VERSION 5.7 ;
  NOWIREEXTENSIONATPIN ON ;
  DIVIDERCHAR "/" ;
  BUSBITCHARS "[]" ;
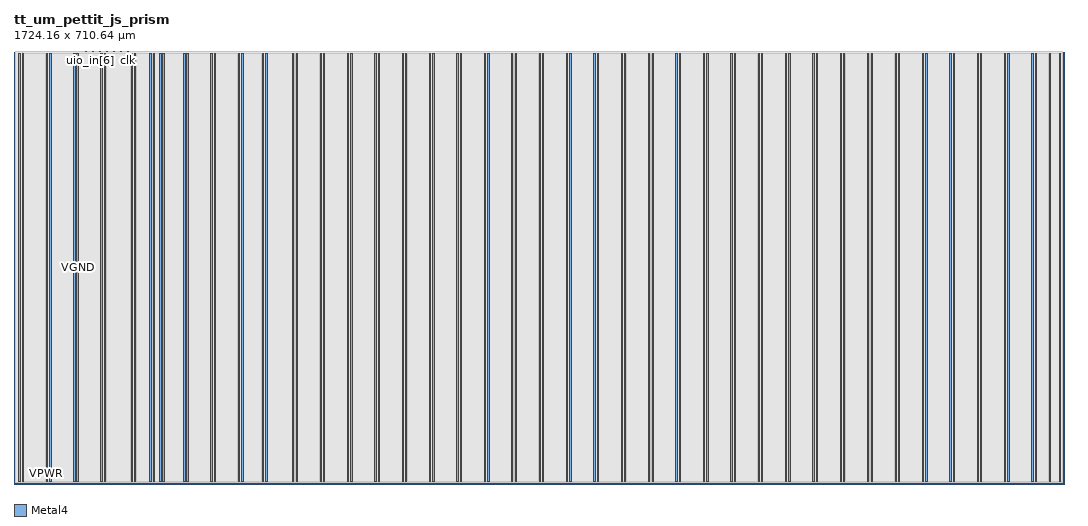
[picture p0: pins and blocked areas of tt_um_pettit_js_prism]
MACRO tt_um_pettit_js_prism
  CLASS BLOCK ;
  FOREIGN tt_um_pettit_js_prism ;
  ORIGIN 0.000 0.000 ;
  SIZE 1724.160 BY 710.640 ;
  PIN VGND
    DIRECTION INOUT ;
    USE GROUND ;
    PORT
      LAYER Metal4 ;
        RECT 13.240 3.780 16.050 706.860 ;
    END
    PORT
      LAYER Metal4 ;
        RECT 58.200 3.780 61.010 706.860 ;
    END
    PORT
      LAYER Metal4 ;
        RECT 103.160 3.780 105.970 706.860 ;
    END
    PORT
      LAYER Metal4 ;
        RECT 148.120 3.780 150.930 706.860 ;
    END
    PORT
      LAYER Metal4 ;
        RECT 192.250 3.780 195.060 706.860 ;
    END
    PORT
      LAYER Metal4 ;
        RECT 228.300 3.780 231.110 706.860 ;
    END
    PORT
      LAYER Metal4 ;
        RECT 238.710 3.780 241.520 706.860 ;
    END
    PORT
      LAYER Metal4 ;
        RECT 283.670 3.780 286.480 706.860 ;
    END
    PORT
      LAYER Metal4 ;
        RECT 328.630 3.780 331.440 706.860 ;
    END
    PORT
      LAYER Metal4 ;
        RECT 373.590 3.780 376.400 706.860 ;
    END
    PORT
      LAYER Metal4 ;
        RECT 407.310 3.780 410.120 706.860 ;
    END
    PORT
      LAYER Metal4 ;
        RECT 463.200 3.560 465.300 707.080 ;
    END
    PORT
      LAYER Metal4 ;
        RECT 508.160 3.560 510.260 707.080 ;
    END
    PORT
      LAYER Metal4 ;
        RECT 553.120 3.780 555.220 706.860 ;
    END
    PORT
      LAYER Metal4 ;
        RECT 598.080 3.780 600.180 706.860 ;
    END
    PORT
      LAYER Metal4 ;
        RECT 643.040 3.780 645.140 706.860 ;
    END
    PORT
      LAYER Metal4 ;
        RECT 688.000 3.780 690.100 706.860 ;
    END
    PORT
      LAYER Metal4 ;
        RECT 732.960 3.780 735.060 706.860 ;
    END
    PORT
      LAYER Metal4 ;
        RECT 777.920 3.780 780.020 706.860 ;
    END
    PORT
      LAYER Metal4 ;
        RECT 822.880 3.780 824.980 706.860 ;
    END
    PORT
      LAYER Metal4 ;
        RECT 867.840 3.560 869.940 707.080 ;
    END
    PORT
      LAYER Metal4 ;
        RECT 912.800 3.560 914.900 707.080 ;
    END
    PORT
      LAYER Metal4 ;
        RECT 957.760 3.560 959.860 707.080 ;
    END
    PORT
      LAYER Metal4 ;
        RECT 1002.720 3.560 1004.820 707.080 ;
    END
    PORT
      LAYER Metal4 ;
        RECT 1047.680 3.560 1049.780 707.080 ;
    END
    PORT
      LAYER Metal4 ;
        RECT 1092.640 3.560 1094.740 707.080 ;
    END
    PORT
      LAYER Metal4 ;
        RECT 1137.600 3.560 1139.700 707.080 ;
    END
    PORT
      LAYER Metal4 ;
        RECT 1182.560 3.560 1184.660 707.080 ;
    END
    PORT
      LAYER Metal4 ;
        RECT 1227.520 3.560 1229.620 707.080 ;
    END
    PORT
      LAYER Metal4 ;
        RECT 1272.480 3.560 1274.580 707.080 ;
    END
    PORT
      LAYER Metal4 ;
        RECT 1317.440 3.560 1319.540 707.080 ;
    END
    PORT
      LAYER Metal4 ;
        RECT 1362.400 3.780 1364.500 706.860 ;
    END
    PORT
      LAYER Metal4 ;
        RECT 1407.360 3.780 1409.460 706.860 ;
    END
    PORT
      LAYER Metal4 ;
        RECT 1452.320 3.780 1454.420 706.860 ;
    END
    PORT
      LAYER Metal4 ;
        RECT 1497.280 3.780 1499.380 706.860 ;
    END
    PORT
      LAYER Metal4 ;
        RECT 1542.240 3.780 1544.340 706.860 ;
    END
    PORT
      LAYER Metal4 ;
        RECT 1587.200 3.780 1589.300 706.860 ;
    END
    PORT
      LAYER Metal4 ;
        RECT 1632.160 3.780 1634.260 706.860 ;
    END
    PORT
      LAYER Metal4 ;
        RECT 1677.120 3.560 1679.220 707.080 ;
    END
    PORT
      LAYER Metal4 ;
        RECT 1699.590 3.780 1701.690 706.860 ;
    END
  END VGND
  PIN VPWR
    DIRECTION INOUT ;
    USE POWER ;
    PORT
      LAYER Metal4 ;
        RECT 7.620 3.780 10.430 706.860 ;
    END
    PORT
      LAYER Metal4 ;
        RECT 52.580 3.780 55.390 706.860 ;
    END
    PORT
      LAYER Metal4 ;
        RECT 97.540 3.780 100.350 706.860 ;
    END
    PORT
      LAYER Metal4 ;
        RECT 142.500 3.780 145.310 706.860 ;
    END
    PORT
      LAYER Metal4 ;
        RECT 197.400 3.780 200.210 706.860 ;
    END
    PORT
      LAYER Metal4 ;
        RECT 223.150 3.780 225.960 706.860 ;
    END
    PORT
      LAYER Metal4 ;
        RECT 244.330 3.780 247.140 706.860 ;
    END
    PORT
      LAYER Metal4 ;
        RECT 278.050 3.780 280.860 706.860 ;
    END
    PORT
      LAYER Metal4 ;
        RECT 323.010 3.780 325.820 706.860 ;
    END
    PORT
      LAYER Metal4 ;
        RECT 367.970 3.780 370.780 706.860 ;
    END
    PORT
      LAYER Metal4 ;
        RECT 412.930 3.780 415.740 706.860 ;
    END
    PORT
      LAYER Metal4 ;
        RECT 457.580 3.560 459.680 707.080 ;
    END
    PORT
      LAYER Metal4 ;
        RECT 502.540 3.560 504.640 707.080 ;
    END
    PORT
      LAYER Metal4 ;
        RECT 547.500 3.780 549.600 706.860 ;
    END
    PORT
      LAYER Metal4 ;
        RECT 592.460 3.780 594.560 706.860 ;
    END
    PORT
      LAYER Metal4 ;
        RECT 637.420 3.780 639.520 706.860 ;
    END
    PORT
      LAYER Metal4 ;
        RECT 682.380 3.780 684.480 706.860 ;
    END
    PORT
      LAYER Metal4 ;
        RECT 727.340 3.780 729.440 706.860 ;
    END
    PORT
      LAYER Metal4 ;
        RECT 772.300 3.780 774.400 706.860 ;
    END
    PORT
      LAYER Metal4 ;
        RECT 817.260 3.780 819.360 706.860 ;
    END
    PORT
      LAYER Metal4 ;
        RECT 862.220 3.780 864.320 706.860 ;
    END
    PORT
      LAYER Metal4 ;
        RECT 907.180 3.560 909.280 707.080 ;
    END
    PORT
      LAYER Metal4 ;
        RECT 952.140 3.560 954.240 707.080 ;
    END
    PORT
      LAYER Metal4 ;
        RECT 997.100 3.560 999.200 707.080 ;
    END
    PORT
      LAYER Metal4 ;
        RECT 1042.060 3.560 1044.160 707.080 ;
    END
    PORT
      LAYER Metal4 ;
        RECT 1087.020 3.560 1089.120 707.080 ;
    END
    PORT
      LAYER Metal4 ;
        RECT 1131.980 3.560 1134.080 707.080 ;
    END
    PORT
      LAYER Metal4 ;
        RECT 1176.940 3.560 1179.040 707.080 ;
    END
    PORT
      LAYER Metal4 ;
        RECT 1221.900 3.560 1224.000 707.080 ;
    END
    PORT
      LAYER Metal4 ;
        RECT 1266.860 3.560 1268.960 707.080 ;
    END
    PORT
      LAYER Metal4 ;
        RECT 1311.820 3.560 1313.920 707.080 ;
    END
    PORT
      LAYER Metal4 ;
        RECT 1356.780 3.780 1358.880 706.860 ;
    END
    PORT
      LAYER Metal4 ;
        RECT 1401.740 3.780 1403.840 706.860 ;
    END
    PORT
      LAYER Metal4 ;
        RECT 1446.700 3.780 1448.800 706.860 ;
    END
    PORT
      LAYER Metal4 ;
        RECT 1491.660 3.780 1493.760 706.860 ;
    END
    PORT
      LAYER Metal4 ;
        RECT 1536.620 3.780 1538.720 706.860 ;
    END
    PORT
      LAYER Metal4 ;
        RECT 1581.580 3.780 1583.680 706.860 ;
    END
    PORT
      LAYER Metal4 ;
        RECT 1626.540 3.780 1628.640 706.860 ;
    END
    PORT
      LAYER Metal4 ;
        RECT 1671.500 3.780 1673.600 706.860 ;
    END
    PORT
      LAYER Metal4 ;
        RECT 1716.460 3.560 1718.560 707.080 ;
    END
  END VPWR
  PIN clk
    DIRECTION INPUT ;
    USE SIGNAL ;
    ANTENNAGATEAREA 1.450800 ;
    PORT
      LAYER Metal4 ;
        RECT 187.050 709.640 187.350 710.640 ;
    END
  END clk
  PIN ena
    DIRECTION INPUT ;
    USE SIGNAL ;
    PORT
      LAYER Metal4 ;
        RECT 190.890 709.640 191.190 710.640 ;
    END
  END ena
  PIN rst_n
    DIRECTION INPUT ;
    USE SIGNAL ;
    ANTENNAGATEAREA 0.180700 ;
    PORT
      LAYER Metal4 ;
        RECT 183.210 709.640 183.510 710.640 ;
    END
  END rst_n
  PIN ui_in[0]
    DIRECTION INPUT ;
    USE SIGNAL ;
    ANTENNAGATEAREA 0.180700 ;
    PORT
      LAYER Metal4 ;
        RECT 179.370 709.640 179.670 710.640 ;
    END
  END ui_in[0]
  PIN ui_in[1]
    DIRECTION INPUT ;
    USE SIGNAL ;
    ANTENNAGATEAREA 0.180700 ;
    PORT
      LAYER Metal4 ;
        RECT 175.530 709.640 175.830 710.640 ;
    END
  END ui_in[1]
  PIN ui_in[2]
    DIRECTION INPUT ;
    USE SIGNAL ;
    ANTENNAGATEAREA 0.180700 ;
    PORT
      LAYER Metal4 ;
        RECT 171.690 709.640 171.990 710.640 ;
    END
  END ui_in[2]
  PIN ui_in[3]
    DIRECTION INPUT ;
    USE SIGNAL ;
    ANTENNAGATEAREA 0.180700 ;
    PORT
      LAYER Metal4 ;
        RECT 167.850 709.640 168.150 710.640 ;
    END
  END ui_in[3]
  PIN ui_in[4]
    DIRECTION INPUT ;
    USE SIGNAL ;
    ANTENNAGATEAREA 0.180700 ;
    PORT
      LAYER Metal4 ;
        RECT 164.010 709.640 164.310 710.640 ;
    END
  END ui_in[4]
  PIN ui_in[5]
    DIRECTION INPUT ;
    USE SIGNAL ;
    ANTENNAGATEAREA 0.180700 ;
    PORT
      LAYER Metal4 ;
        RECT 160.170 709.640 160.470 710.640 ;
    END
  END ui_in[5]
  PIN ui_in[6]
    DIRECTION INPUT ;
    USE SIGNAL ;
    ANTENNAGATEAREA 0.180700 ;
    PORT
      LAYER Metal4 ;
        RECT 156.330 709.640 156.630 710.640 ;
    END
  END ui_in[6]
  PIN ui_in[7]
    DIRECTION INPUT ;
    USE SIGNAL ;
    ANTENNAGATEAREA 0.180700 ;
    PORT
      LAYER Metal4 ;
        RECT 152.490 709.640 152.790 710.640 ;
    END
  END ui_in[7]
  PIN uio_in[0]
    DIRECTION INPUT ;
    USE SIGNAL ;
    PORT
      LAYER Metal4 ;
        RECT 148.650 709.640 148.950 710.640 ;
    END
  END uio_in[0]
  PIN uio_in[1]
    DIRECTION INPUT ;
    USE SIGNAL ;
    ANTENNAGATEAREA 0.180700 ;
    PORT
      LAYER Metal4 ;
        RECT 144.810 709.640 145.110 710.640 ;
    END
  END uio_in[1]
  PIN uio_in[2]
    DIRECTION INPUT ;
    USE SIGNAL ;
    ANTENNAGATEAREA 0.180700 ;
    PORT
      LAYER Metal4 ;
        RECT 140.970 709.640 141.270 710.640 ;
    END
  END uio_in[2]
  PIN uio_in[3]
    DIRECTION INPUT ;
    USE SIGNAL ;
    PORT
      LAYER Metal4 ;
        RECT 137.130 709.640 137.430 710.640 ;
    END
  END uio_in[3]
  PIN uio_in[4]
    DIRECTION INPUT ;
    USE SIGNAL ;
    ANTENNAGATEAREA 0.180700 ;
    PORT
      LAYER Metal4 ;
        RECT 133.290 709.640 133.590 710.640 ;
    END
  END uio_in[4]
  PIN uio_in[5]
    DIRECTION INPUT ;
    USE SIGNAL ;
    ANTENNAGATEAREA 0.180700 ;
    PORT
      LAYER Metal4 ;
        RECT 129.450 709.640 129.750 710.640 ;
    END
  END uio_in[5]
  PIN uio_in[6]
    DIRECTION INPUT ;
    USE SIGNAL ;
    PORT
      LAYER Metal4 ;
        RECT 125.610 709.640 125.910 710.640 ;
    END
  END uio_in[6]
  PIN uio_in[7]
    DIRECTION INPUT ;
    USE SIGNAL ;
    PORT
      LAYER Metal4 ;
        RECT 121.770 709.640 122.070 710.640 ;
    END
  END uio_in[7]
  PIN uio_oe[0]
    DIRECTION OUTPUT ;
    USE SIGNAL ;
    ANTENNADIFFAREA 0.632400 ;
    PORT
      LAYER Metal4 ;
        RECT 56.490 709.640 56.790 710.640 ;
    END
  END uio_oe[0]
  PIN uio_oe[1]
    DIRECTION OUTPUT ;
    USE SIGNAL ;
    ANTENNADIFFAREA 0.632400 ;
    PORT
      LAYER Metal4 ;
        RECT 52.650 709.640 52.950 710.640 ;
    END
  END uio_oe[1]
  PIN uio_oe[2]
    DIRECTION OUTPUT ;
    USE SIGNAL ;
    ANTENNADIFFAREA 0.632400 ;
    PORT
      LAYER Metal4 ;
        RECT 48.810 709.640 49.110 710.640 ;
    END
  END uio_oe[2]
  PIN uio_oe[3]
    DIRECTION OUTPUT ;
    USE SIGNAL ;
    ANTENNADIFFAREA 0.632400 ;
    PORT
      LAYER Metal4 ;
        RECT 44.970 709.640 45.270 710.640 ;
    END
  END uio_oe[3]
  PIN uio_oe[4]
    DIRECTION OUTPUT ;
    USE SIGNAL ;
    ANTENNADIFFAREA 0.632400 ;
    PORT
      LAYER Metal4 ;
        RECT 41.130 709.640 41.430 710.640 ;
    END
  END uio_oe[4]
  PIN uio_oe[5]
    DIRECTION OUTPUT ;
    USE SIGNAL ;
    ANTENNADIFFAREA 0.632400 ;
    PORT
      LAYER Metal4 ;
        RECT 37.290 709.640 37.590 710.640 ;
    END
  END uio_oe[5]
  PIN uio_oe[6]
    DIRECTION OUTPUT ;
    USE SIGNAL ;
    ANTENNADIFFAREA 0.632400 ;
    PORT
      LAYER Metal4 ;
        RECT 33.450 709.640 33.750 710.640 ;
    END
  END uio_oe[6]
  PIN uio_oe[7]
    DIRECTION OUTPUT ;
    USE SIGNAL ;
    ANTENNADIFFAREA 0.632400 ;
    PORT
      LAYER Metal4 ;
        RECT 29.610 709.640 29.910 710.640 ;
    END
  END uio_oe[7]
  PIN uio_out[0]
    DIRECTION OUTPUT ;
    USE SIGNAL ;
    ANTENNAGATEAREA 0.470600 ;
    ANTENNADIFFAREA 0.632400 ;
    PORT
      LAYER Metal4 ;
        RECT 87.210 709.640 87.510 710.640 ;
    END
  END uio_out[0]
  PIN uio_out[1]
    DIRECTION OUTPUT ;
    USE SIGNAL ;
    ANTENNADIFFAREA 0.677200 ;
    PORT
      LAYER Metal4 ;
        RECT 83.370 709.640 83.670 710.640 ;
    END
  END uio_out[1]
  PIN uio_out[2]
    DIRECTION OUTPUT ;
    USE SIGNAL ;
    ANTENNADIFFAREA 1.413600 ;
    PORT
      LAYER Metal4 ;
        RECT 79.530 709.640 79.830 710.640 ;
    END
  END uio_out[2]
  PIN uio_out[3]
    DIRECTION OUTPUT ;
    USE SIGNAL ;
    ANTENNADIFFAREA 1.008100 ;
    PORT
      LAYER Metal4 ;
        RECT 75.690 709.640 75.990 710.640 ;
    END
  END uio_out[3]
  PIN uio_out[4]
    DIRECTION OUTPUT ;
    USE SIGNAL ;
    ANTENNADIFFAREA 0.632400 ;
    PORT
      LAYER Metal4 ;
        RECT 71.850 709.640 72.150 710.640 ;
    END
  END uio_out[4]
  PIN uio_out[5]
    DIRECTION OUTPUT ;
    USE SIGNAL ;
    ANTENNADIFFAREA 0.677200 ;
    PORT
      LAYER Metal4 ;
        RECT 68.010 709.640 68.310 710.640 ;
    END
  END uio_out[5]
  PIN uio_out[6]
    DIRECTION OUTPUT ;
    USE SIGNAL ;
    ANTENNAGATEAREA 0.351000 ;
    ANTENNADIFFAREA 0.632400 ;
    PORT
      LAYER Metal4 ;
        RECT 64.170 709.640 64.470 710.640 ;
    END
  END uio_out[6]
  PIN uio_out[7]
    DIRECTION OUTPUT ;
    USE SIGNAL ;
    ANTENNAGATEAREA 0.109200 ;
    ANTENNADIFFAREA 0.632400 ;
    PORT
      LAYER Metal4 ;
        RECT 60.330 709.640 60.630 710.640 ;
    END
  END uio_out[7]
  PIN uo_out[0]
    DIRECTION OUTPUT ;
    USE SIGNAL ;
    ANTENNADIFFAREA 0.706800 ;
    PORT
      LAYER Metal4 ;
        RECT 117.930 709.640 118.230 710.640 ;
    END
  END uo_out[0]
  PIN uo_out[1]
    DIRECTION OUTPUT ;
    USE SIGNAL ;
    ANTENNADIFFAREA 0.706800 ;
    PORT
      LAYER Metal4 ;
        RECT 114.090 709.640 114.390 710.640 ;
    END
  END uo_out[1]
  PIN uo_out[2]
    DIRECTION OUTPUT ;
    USE SIGNAL ;
    ANTENNADIFFAREA 0.632400 ;
    PORT
      LAYER Metal4 ;
        RECT 110.250 709.640 110.550 710.640 ;
    END
  END uo_out[2]
  PIN uo_out[3]
    DIRECTION OUTPUT ;
    USE SIGNAL ;
    ANTENNADIFFAREA 2.827200 ;
    PORT
      LAYER Metal4 ;
        RECT 106.410 709.640 106.710 710.640 ;
    END
  END uo_out[3]
  PIN uo_out[4]
    DIRECTION OUTPUT ;
    USE SIGNAL ;
    ANTENNADIFFAREA 0.632400 ;
    PORT
      LAYER Metal4 ;
        RECT 102.570 709.640 102.870 710.640 ;
    END
  END uo_out[4]
  PIN uo_out[5]
    DIRECTION OUTPUT ;
    USE SIGNAL ;
    ANTENNADIFFAREA 0.632400 ;
    PORT
      LAYER Metal4 ;
        RECT 98.730 709.640 99.030 710.640 ;
    END
  END uo_out[5]
  PIN uo_out[6]
    DIRECTION OUTPUT ;
    USE SIGNAL ;
    ANTENNADIFFAREA 0.706800 ;
    PORT
      LAYER Metal4 ;
        RECT 94.890 709.640 95.190 710.640 ;
    END
  END uo_out[6]
  PIN uo_out[7]
    DIRECTION OUTPUT ;
    USE SIGNAL ;
    ANTENNADIFFAREA 0.706800 ;
    PORT
      LAYER Metal4 ;
        RECT 91.050 709.640 91.350 710.640 ;
    END
  END uo_out[7]
  OBS
      LAYER GatPoly ;
        RECT 2.880 3.630 1721.280 707.010 ;
      LAYER Metal1 ;
        RECT 2.880 3.560 1721.280 707.080 ;
      LAYER Metal2 ;
        RECT 2.295 2.375 1721.865 709.525 ;
      LAYER Metal3 ;
        RECT 2.255 2.415 1721.905 709.485 ;
      LAYER Metal4 ;
        RECT 13.595 709.430 29.400 709.640 ;
        RECT 30.120 709.430 33.240 709.640 ;
        RECT 33.960 709.430 37.080 709.640 ;
        RECT 37.800 709.430 40.920 709.640 ;
        RECT 41.640 709.430 44.760 709.640 ;
        RECT 45.480 709.430 48.600 709.640 ;
        RECT 49.320 709.430 52.440 709.640 ;
        RECT 53.160 709.430 56.280 709.640 ;
        RECT 57.000 709.430 60.120 709.640 ;
        RECT 60.840 709.430 63.960 709.640 ;
        RECT 64.680 709.430 67.800 709.640 ;
        RECT 68.520 709.430 71.640 709.640 ;
        RECT 72.360 709.430 75.480 709.640 ;
        RECT 76.200 709.430 79.320 709.640 ;
        RECT 80.040 709.430 83.160 709.640 ;
        RECT 83.880 709.430 87.000 709.640 ;
        RECT 87.720 709.430 90.840 709.640 ;
        RECT 91.560 709.430 94.680 709.640 ;
        RECT 95.400 709.430 98.520 709.640 ;
        RECT 99.240 709.430 102.360 709.640 ;
        RECT 103.080 709.430 106.200 709.640 ;
        RECT 106.920 709.430 110.040 709.640 ;
        RECT 110.760 709.430 113.880 709.640 ;
        RECT 114.600 709.430 117.720 709.640 ;
        RECT 118.440 709.430 121.560 709.640 ;
        RECT 122.280 709.430 125.400 709.640 ;
        RECT 126.120 709.430 129.240 709.640 ;
        RECT 129.960 709.430 133.080 709.640 ;
        RECT 133.800 709.430 136.920 709.640 ;
        RECT 137.640 709.430 140.760 709.640 ;
        RECT 141.480 709.430 144.600 709.640 ;
        RECT 145.320 709.430 148.440 709.640 ;
        RECT 149.160 709.430 152.280 709.640 ;
        RECT 153.000 709.430 156.120 709.640 ;
        RECT 156.840 709.430 159.960 709.640 ;
        RECT 160.680 709.430 163.800 709.640 ;
        RECT 164.520 709.430 167.640 709.640 ;
        RECT 168.360 709.430 171.480 709.640 ;
        RECT 172.200 709.430 175.320 709.640 ;
        RECT 176.040 709.430 179.160 709.640 ;
        RECT 179.880 709.430 183.000 709.640 ;
        RECT 183.720 709.430 186.840 709.640 ;
        RECT 187.560 709.430 190.680 709.640 ;
        RECT 191.400 709.430 1720.900 709.640 ;
        RECT 13.595 707.290 1720.900 709.430 ;
        RECT 13.595 707.070 457.370 707.290 ;
        RECT 16.260 3.570 52.370 707.070 ;
        RECT 55.600 3.570 57.990 707.070 ;
        RECT 61.220 3.570 97.330 707.070 ;
        RECT 100.560 3.570 102.950 707.070 ;
        RECT 106.180 3.570 142.290 707.070 ;
        RECT 145.520 3.570 147.910 707.070 ;
        RECT 151.140 3.570 192.040 707.070 ;
        RECT 195.270 3.570 197.190 707.070 ;
        RECT 200.420 3.570 222.940 707.070 ;
        RECT 226.170 3.570 228.090 707.070 ;
        RECT 231.320 3.570 238.500 707.070 ;
        RECT 241.730 3.570 244.120 707.070 ;
        RECT 247.350 3.570 277.840 707.070 ;
        RECT 281.070 3.570 283.460 707.070 ;
        RECT 286.690 3.570 322.800 707.070 ;
        RECT 326.030 3.570 328.420 707.070 ;
        RECT 331.650 3.570 367.760 707.070 ;
        RECT 370.990 3.570 373.380 707.070 ;
        RECT 376.610 3.570 407.100 707.070 ;
        RECT 410.330 3.570 412.720 707.070 ;
        RECT 415.950 3.570 457.370 707.070 ;
        RECT 13.595 3.350 457.370 3.570 ;
        RECT 459.890 3.350 462.990 707.290 ;
        RECT 465.510 3.350 502.330 707.290 ;
        RECT 504.850 3.350 507.950 707.290 ;
        RECT 510.470 707.070 867.630 707.290 ;
        RECT 510.470 3.570 547.290 707.070 ;
        RECT 549.810 3.570 552.910 707.070 ;
        RECT 555.430 3.570 592.250 707.070 ;
        RECT 594.770 3.570 597.870 707.070 ;
        RECT 600.390 3.570 637.210 707.070 ;
        RECT 639.730 3.570 642.830 707.070 ;
        RECT 645.350 3.570 682.170 707.070 ;
        RECT 684.690 3.570 687.790 707.070 ;
        RECT 690.310 3.570 727.130 707.070 ;
        RECT 729.650 3.570 732.750 707.070 ;
        RECT 735.270 3.570 772.090 707.070 ;
        RECT 774.610 3.570 777.710 707.070 ;
        RECT 780.230 3.570 817.050 707.070 ;
        RECT 819.570 3.570 822.670 707.070 ;
        RECT 825.190 3.570 862.010 707.070 ;
        RECT 864.530 3.570 867.630 707.070 ;
        RECT 510.470 3.350 867.630 3.570 ;
        RECT 870.150 3.350 906.970 707.290 ;
        RECT 909.490 3.350 912.590 707.290 ;
        RECT 915.110 3.350 951.930 707.290 ;
        RECT 954.450 3.350 957.550 707.290 ;
        RECT 960.070 3.350 996.890 707.290 ;
        RECT 999.410 3.350 1002.510 707.290 ;
        RECT 1005.030 3.350 1041.850 707.290 ;
        RECT 1044.370 3.350 1047.470 707.290 ;
        RECT 1049.990 3.350 1086.810 707.290 ;
        RECT 1089.330 3.350 1092.430 707.290 ;
        RECT 1094.950 3.350 1131.770 707.290 ;
        RECT 1134.290 3.350 1137.390 707.290 ;
        RECT 1139.910 3.350 1176.730 707.290 ;
        RECT 1179.250 3.350 1182.350 707.290 ;
        RECT 1184.870 3.350 1221.690 707.290 ;
        RECT 1224.210 3.350 1227.310 707.290 ;
        RECT 1229.830 3.350 1266.650 707.290 ;
        RECT 1269.170 3.350 1272.270 707.290 ;
        RECT 1274.790 3.350 1311.610 707.290 ;
        RECT 1314.130 3.350 1317.230 707.290 ;
        RECT 1319.750 707.070 1676.910 707.290 ;
        RECT 1319.750 3.570 1356.570 707.070 ;
        RECT 1359.090 3.570 1362.190 707.070 ;
        RECT 1364.710 3.570 1401.530 707.070 ;
        RECT 1404.050 3.570 1407.150 707.070 ;
        RECT 1409.670 3.570 1446.490 707.070 ;
        RECT 1449.010 3.570 1452.110 707.070 ;
        RECT 1454.630 3.570 1491.450 707.070 ;
        RECT 1493.970 3.570 1497.070 707.070 ;
        RECT 1499.590 3.570 1536.410 707.070 ;
        RECT 1538.930 3.570 1542.030 707.070 ;
        RECT 1544.550 3.570 1581.370 707.070 ;
        RECT 1583.890 3.570 1586.990 707.070 ;
        RECT 1589.510 3.570 1626.330 707.070 ;
        RECT 1628.850 3.570 1631.950 707.070 ;
        RECT 1634.470 3.570 1671.290 707.070 ;
        RECT 1673.810 3.570 1676.910 707.070 ;
        RECT 1319.750 3.350 1676.910 3.570 ;
        RECT 1679.430 707.070 1716.250 707.290 ;
        RECT 1679.430 3.570 1699.380 707.070 ;
        RECT 1701.900 3.570 1716.250 707.070 ;
        RECT 1679.430 3.350 1716.250 3.570 ;
        RECT 1718.770 3.350 1720.900 707.290 ;
        RECT 13.595 2.375 1720.900 3.350 ;
  END
END tt_um_pettit_js_prism
END LIBRARY

